VERSION 5.7 ;
  NOWIREEXTENSIONATPIN ON ;
  DIVIDERCHAR "/" ;
  BUSBITCHARS "[]" ;
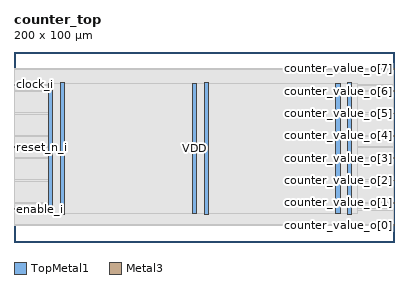
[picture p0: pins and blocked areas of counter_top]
MACRO counter_top
  CLASS BLOCK ;
  FOREIGN counter_top ;
  ORIGIN 0.000 0.000 ;
  SIZE 200.000 BY 100.000 ;
  PIN VDD
    DIRECTION INOUT ;
    USE POWER ;
    PORT
      LAYER TopMetal1 ;
        RECT 18.260 14.900 20.460 83.380 ;
    END
    PORT
      LAYER TopMetal1 ;
        RECT 93.860 14.900 96.060 83.380 ;
    END
    PORT
      LAYER TopMetal1 ;
        RECT 169.460 14.900 171.660 83.380 ;
    END
  END VDD
  PIN VSS
    DIRECTION INOUT ;
    USE GROUND ;
    PORT
      LAYER TopMetal1 ;
        RECT 24.460 14.490 26.660 83.790 ;
    END
    PORT
      LAYER TopMetal1 ;
        RECT 100.060 14.490 102.260 83.790 ;
    END
    PORT
      LAYER TopMetal1 ;
        RECT 175.660 14.490 177.860 83.790 ;
    END
  END VSS
  PIN clock_i
    DIRECTION INPUT ;
    USE SIGNAL ;
    ANTENNAGATEAREA 1.450800 ;
    PORT
      LAYER Metal3 ;
        RECT 0.000 82.540 0.400 82.940 ;
    END
  END clock_i
  PIN counter_value_o[0]
    DIRECTION OUTPUT ;
    USE SIGNAL ;
    ANTENNADIFFAREA 0.708600 ;
    PORT
      LAYER Metal3 ;
        RECT 199.600 8.620 200.000 9.020 ;
    END
  END counter_value_o[0]
  PIN counter_value_o[1]
    DIRECTION OUTPUT ;
    USE SIGNAL ;
    ANTENNADIFFAREA 0.708600 ;
    PORT
      LAYER Metal3 ;
        RECT 199.600 20.380 200.000 20.780 ;
    END
  END counter_value_o[1]
  PIN counter_value_o[2]
    DIRECTION OUTPUT ;
    USE SIGNAL ;
    ANTENNADIFFAREA 0.708600 ;
    PORT
      LAYER Metal3 ;
        RECT 199.600 32.140 200.000 32.540 ;
    END
  END counter_value_o[2]
  PIN counter_value_o[3]
    DIRECTION OUTPUT ;
    USE SIGNAL ;
    ANTENNADIFFAREA 0.708600 ;
    PORT
      LAYER Metal3 ;
        RECT 199.600 43.900 200.000 44.300 ;
    END
  END counter_value_o[3]
  PIN counter_value_o[4]
    DIRECTION OUTPUT ;
    USE SIGNAL ;
    ANTENNADIFFAREA 0.708600 ;
    PORT
      LAYER Metal3 ;
        RECT 199.600 55.660 200.000 56.060 ;
    END
  END counter_value_o[4]
  PIN counter_value_o[5]
    DIRECTION OUTPUT ;
    USE SIGNAL ;
    ANTENNADIFFAREA 0.708600 ;
    PORT
      LAYER Metal3 ;
        RECT 199.600 67.420 200.000 67.820 ;
    END
  END counter_value_o[5]
  PIN counter_value_o[6]
    DIRECTION OUTPUT ;
    USE SIGNAL ;
    ANTENNADIFFAREA 0.708600 ;
    PORT
      LAYER Metal3 ;
        RECT 199.600 79.180 200.000 79.580 ;
    END
  END counter_value_o[6]
  PIN counter_value_o[7]
    DIRECTION OUTPUT ;
    USE SIGNAL ;
    ANTENNADIFFAREA 0.708600 ;
    PORT
      LAYER Metal3 ;
        RECT 199.600 90.940 200.000 91.340 ;
    END
  END counter_value_o[7]
  PIN enable_i
    DIRECTION INPUT ;
    USE SIGNAL ;
    ANTENNAGATEAREA 0.180700 ;
    PORT
      LAYER Metal3 ;
        RECT 0.000 17.020 0.400 17.420 ;
    END
  END enable_i
  PIN reset_n_i
    DIRECTION INPUT ;
    USE SIGNAL ;
    ANTENNAGATEAREA 0.180700 ;
    PORT
      LAYER Metal3 ;
        RECT 0.000 49.780 0.400 50.180 ;
    END
  END reset_n_i
  OBS
      LAYER GatPoly ;
        RECT 5.760 14.970 193.920 83.310 ;
      LAYER Metal1 ;
        RECT 5.760 14.900 193.920 83.380 ;
      LAYER Metal2 ;
        RECT 6.135 8.675 193.545 91.285 ;
      LAYER Metal3 ;
        RECT 0.400 90.730 199.390 91.240 ;
        RECT 0.400 83.150 199.600 90.730 ;
        RECT 0.610 82.330 199.600 83.150 ;
        RECT 0.400 79.790 199.600 82.330 ;
        RECT 0.400 78.970 199.390 79.790 ;
        RECT 0.400 68.030 199.600 78.970 ;
        RECT 0.400 67.210 199.390 68.030 ;
        RECT 0.400 56.270 199.600 67.210 ;
        RECT 0.400 55.450 199.390 56.270 ;
        RECT 0.400 50.390 199.600 55.450 ;
        RECT 0.610 49.570 199.600 50.390 ;
        RECT 0.400 44.510 199.600 49.570 ;
        RECT 0.400 43.690 199.390 44.510 ;
        RECT 0.400 32.750 199.600 43.690 ;
        RECT 0.400 31.930 199.390 32.750 ;
        RECT 0.400 20.990 199.600 31.930 ;
        RECT 0.400 20.170 199.390 20.990 ;
        RECT 0.400 17.630 199.600 20.170 ;
        RECT 0.610 16.810 199.600 17.630 ;
        RECT 0.400 9.230 199.600 16.810 ;
        RECT 0.400 8.720 199.390 9.230 ;
      LAYER Metal4 ;
        RECT 18.440 14.975 180.580 83.305 ;
      LAYER Metal5 ;
        RECT 18.395 14.810 177.725 83.470 ;
  END
END counter_top
END LIBRARY

